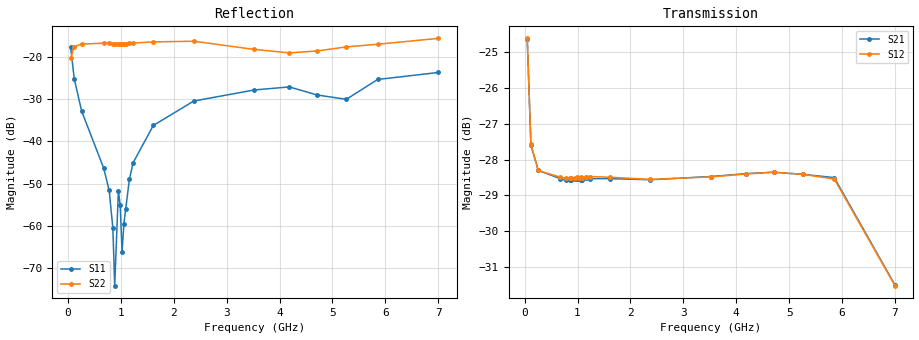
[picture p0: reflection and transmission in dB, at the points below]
! Integrated Device Technology
! Corporate Headquarters
! 6024 Silver Creek Valley Road
! San Jose, CA 95138  USA
! Phone:  1-408-284-8200
! Toll Free:  1-800-223-1366
! Webpage:  http://www.idt.com/
! Timing and RF Division
! 515 Groton Road, Suite 102
! Westford, MA 01886-6024
! Device:  F2258
! Description: Voltage Variable RF Attenuator
! Frequency:  50.0 -  6000.00 MHz
! Package:  3x3 mm Thin QFN Plastic Package: 16 pin
! Ports:  2 RF, 2 DC
!  Pin  1  = NC
!  Pin  2  = NC
!  Pin  3  = RF2  = Port 2
!  Pin  4  = GND
!  Pin  5  = Vdd
!  Pin  6  = NC
!  Pin  7  = VCTRL
!  Pin  8  = NC
!  Pin  9  = GND
!  Pin 10  = RF1  = Port 1
!  Pin 11  = NC
!  Pin 12  = NC
!  Pin 13  = NC
!  Pin 14  = NC
!  Pin 15  = NC
!  Pin 16  = NC
! Vcntrl:  1.620 Volts
! Vdd:  +3.300 Volts
! Current:  1.162 mA
! Data:  The device was measured on a the F2258 evaluation board which has
!  individual transmission lines to the RF pins.  Data was collected
!  using a calibrated network analyzer.  The evaluation board was
!  de-embedded using a TRL calibration technique.
!  The reference plane is the edge of the package pin.
! Misc:  SN 10
!  Action Tracker AT0285
! Date Measured:  2014-12-10
! Date:  2016-01-13  MJV
! Note:
!  Integrated Device Technology supplies this data as a sample of measured
!  data at the package pin for this product.  Your particular data for this
!  product may vary.
!  Data was taken at 25 degrees C.
!  Integrated Device Technology reserves the right to change this data at anytime.
!Freq_(GHz)  S11M_(dB)  S11P_(deg)  S21M_(dB)  S21P_(deg)  S12M_(dB)  S12P_(deg)  S22M_(dB)  S22P_(deg)
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# GHz S dB R 50
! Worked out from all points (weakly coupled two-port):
!   201 points, 50 MHz to 7 GHz, reference 50 ohm
!   highest |S21| = -24.63 dB at 50 MHz (marker M1); lowest = -31.5 dB at 7 GHz (marker M2)
!   lowest |S11| = -74.2 dB at 884 MHz (marker M3), VSWR 1.00, Z = 50 - j0.0018 ohm
!   |S11| at or under -10 dB: start of sweep to end of sweep
!   |S22| runs from -20.3 to -15.5 dB; largest |S21 - S12| = 0.00046
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0.05  -17.54 -109.6  -24.63 -47.7  -24.61 -47.7  -20.27 -33.7
0.1195  -25.15 -104.2  -27.60 -25.7  -27.57 -25.7  -17.48 -10.2
0.2585  -32.78 -106.0  -28.30 -14.5  -28.30 -14.5  -16.90 -6.8
0.6755  -46.35 -106.7  -28.53 -10.9  -28.49 -10.9  -16.68 -9.9
0.77975  -51.64 -112.9  -28.58 -11.2  -28.51 -11.2  -16.72 -11.3
0.84925  -60.60 -116.8  -28.56 -11.4  -28.51 -11.4  -16.76 -12.3
0.884  -74.25 -174.7  -28.57 -11.6  -28.51 -11.6  -16.77 -13.0
0.9535  -51.77 -132.5  -28.55 -11.9  -28.52 -11.9  -16.96 -13.2
0.98825  -55.17 -143.5  -28.53 -12.0  -28.49 -12.1  -16.94 -14.0
1.023  -66.20 -107.9  -28.55 -12.2  -28.50 -12.2  -16.87 -14.5
1.05775  -59.57 -8.5  -28.58 -12.4  -28.48 -12.4  -16.84 -14.9
1.0925  -55.97 14.6  -28.56 -12.6  -28.50 -12.6  -16.82 -15.3
1.162  -49.02 28.6  -28.52 -13.0  -28.47 -13.0  -16.73 -16.2
1.2315  -45.07 23.8  -28.53 -13.5  -28.47 -13.6  -16.65 -17.1
1.61375  -36.22 25.6  -28.53 -16.8  -28.49 -16.9  -16.38 -21.8
2.37825  -30.42 43.8  -28.56 -23.4  -28.55 -23.4  -16.22 -30.2
3.525  -27.78 89.6  -28.47 -34.0  -28.48 -34.0  -18.17 -49.9
4.18525  -27.07 104.1  -28.39 -40.5  -28.40 -40.5  -18.98 -67.6
4.7065  -28.97 94.5  -28.35 -46.0  -28.35 -46.0  -18.54 -77.4
5.2625  -30.01 51.3  -28.41 -52.2  -28.41 -52.2  -17.56 -80.6
5.85325  -25.30 27.8  -28.50 -60.5  -28.54 -60.4  -16.94 -81.1
7  -23.64 83.7  -31.50 -73.2  -31.52 -73.2  -15.54 -135.7
